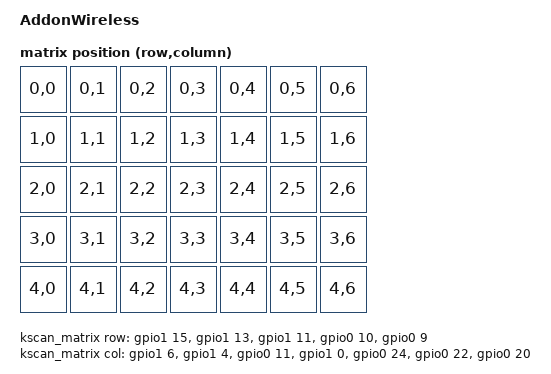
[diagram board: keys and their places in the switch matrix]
/*
 * Copyright (c) 2022 The ZMK Contributors
 *
 * SPDX-License-Identifier: MIT
 */
#include <dt-bindings/zmk/matrix_transform.h>

/ {
    model = "AddonWireless";

    chosen {
        zmk,kscan = &kscan;
        zmk,matrix_transform = &transform;
    };

    transform: transform {
        compatible = "zmk,matrix-transform";
        rows = <5>;
        columns = <7>;

        map = <
         RC(0,0) RC(0,1) RC(0,2) RC(0,3) RC(0,4) RC(0,5) RC(0,6)
         RC(1,0) RC(1,1) RC(1,2) RC(1,3) RC(1,4) RC(1,5) RC(1,6)
         RC(2,0) RC(2,1) RC(2,2) RC(2,3) RC(2,4) RC(2,5) RC(2,6)
         RC(3,0) RC(3,1) RC(3,2) RC(3,3) RC(3,4) RC(3,5) RC(3,6)
         RC(4,0) RC(4,1) RC(4,2) RC(4,3) RC(4,4) RC(4,5) RC(4,6)
        >;
    }; 

    kscan: kscan {
        compatible = "zmk,kscan-composite";
        label = "KSCAN";
        rows = <5>;
        columns = <7>;

        matrix {
            kscan = <&kscan_matrix>;
        };

    };

    kscan_matrix: kscan_matrix {
        compatible = "zmk,kscan-gpio-matrix";
        label = "KSCAN_MATRIX";

        diode-direction = "row2col"; 

        col-gpios
            = <&gpio1 6 (GPIO_ACTIVE_HIGH | GPIO_PULL_DOWN)>
            , <&gpio1 4 (GPIO_ACTIVE_HIGH | GPIO_PULL_DOWN)>
            , <&gpio0 11 (GPIO_ACTIVE_HIGH | GPIO_PULL_DOWN)>
            , <&gpio1 0  (GPIO_ACTIVE_HIGH | GPIO_PULL_DOWN)>
            , <&gpio0 24 (GPIO_ACTIVE_HIGH | GPIO_PULL_DOWN)>
            , <&gpio0 22 (GPIO_ACTIVE_HIGH | GPIO_PULL_DOWN)>
            , <&gpio0 20  (GPIO_ACTIVE_HIGH | GPIO_PULL_DOWN)>
            ;
        row-gpios
            = <&gpio1 15 (GPIO_ACTIVE_HIGH)>
            , <&gpio1 13  (GPIO_ACTIVE_HIGH)>
            , <&gpio1 11 (GPIO_ACTIVE_HIGH)>
            , <&gpio0 10  (GPIO_ACTIVE_HIGH)>
            , <&gpio0 9  (GPIO_ACTIVE_HIGH)>
            ;
    };
    keys
        = <&key_physical_attrs 100 100 100  0 0 0 0>
		, <&key_physical_attrs 100 100 200  0 0 0 0>
		, <&key_physical_attrs 100 100 300  0 0 0 0>
		, <&key_physical_attrs 100 100 400  0 0 0 0>
		, <&key_physical_attrs 100 100 500  0 0 0 0>
		, <&key_physical_attrs 100 100 700  0 0 0 0>

        , <&key_physical_attrs 100 100 100 100 0 0 0>
        , <&key_physical_attrs 100 100 200 100 0 0 0>
        , <&key_physical_attrs 100 100 300 100 0 0 0>
        , <&key_physical_attrs 100 100 400 100 0 0 0>
        , <&key_physical_attrs 100 100 500 100 0 0 0>
        , <&key_physical_attrs 100 100 600 100 0 0 0>
        , <&key_physical_attrs 100 100 700 100 0 0 0>

        , <&key_physical_attrs 100 100 100 200 0 0 0>
        , <&key_physical_attrs 100 100 200 200 0 0 0>
        , <&key_physical_attrs 100 100 300 200 0 0 0>
        , <&key_physical_attrs 100 100 400 200 0 0 0>
        , <&key_physical_attrs 100 100 500 200 0 0 0>
        , <&key_physical_attrs 100 100 600 200 0 0 0>
        , <&key_physical_attrs 100 100 700 200 0 0 0>

        , <&key_physical_attrs 100 100 100 300 0 0 0>
        , <&key_physical_attrs 100 100 200 300 0 0 0>
        , <&key_physical_attrs 100 100 300 300 0 0 0>
        , <&key_physical_attrs 100 100 400 300 0 0 0>
        , <&key_physical_attrs 100 100 500 300 0 0 0>
        , <&key_physical_attrs 100 100 600 300 0 0 0>
        , <&key_physical_attrs 100 100 700 300 0 0 0>

        , <&key_physical_attrs 100 100 100 400 0 0 0>
        , <&key_physical_attrs 100 100 200 400 0 0 0>
        , <&key_physical_attrs 100 100 300 400 0 0 0>
        , <&key_physical_attrs 100 100 400 400 0 0 0>
        , <&key_physical_attrs 100 100 500 400 0 0 0>
        , <&key_physical_attrs 100 100 600 400 0 0 0>
        , <&key_physical_attrs 100 100 700 400 0 0 0>      
    }
};
